VERSION 5.7 ;
  NOWIREEXTENSIONATPIN ON ;
  DIVIDERCHAR "/" ;
  BUSBITCHARS "[]" ;
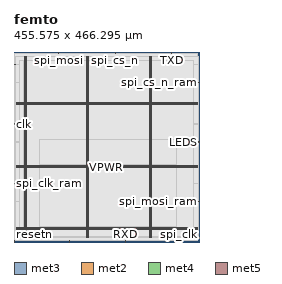
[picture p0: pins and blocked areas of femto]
MACRO femto
  CLASS BLOCK ;
  FOREIGN femto ;
  ORIGIN 0.000 0.000 ;
  SIZE 455.575 BY 466.295 ;
  PIN LEDS
    DIRECTION OUTPUT TRISTATE ;
    USE SIGNAL ;
    ANTENNADIFFAREA 0.445500 ;
    PORT
      LAYER met3 ;
        RECT 451.575 244.840 455.575 245.440 ;
    END
  END LEDS
  PIN RXD
    DIRECTION INPUT ;
    USE SIGNAL ;
    ANTENNAGATEAREA 0.213000 ;
    PORT
      LAYER met2 ;
        RECT 273.790 0.000 274.070 4.000 ;
    END
  END RXD
  PIN TXD
    DIRECTION OUTPUT TRISTATE ;
    USE SIGNAL ;
    ANTENNADIFFAREA 0.795200 ;
    PORT
      LAYER met2 ;
        RECT 386.490 462.295 386.770 466.295 ;
    END
  END TXD
  PIN VGND
    DIRECTION INOUT ;
    USE GROUND ;
    PORT
      LAYER met4 ;
        RECT 28.020 10.640 29.620 454.480 ;
    END
    PORT
      LAYER met4 ;
        RECT 181.620 10.640 183.220 454.480 ;
    END
    PORT
      LAYER met4 ;
        RECT 335.220 10.640 336.820 454.480 ;
    END
    PORT
      LAYER met5 ;
        RECT 5.280 33.380 450.120 34.980 ;
    END
    PORT
      LAYER met5 ;
        RECT 5.280 186.560 450.120 188.160 ;
    END
    PORT
      LAYER met5 ;
        RECT 5.280 339.740 450.120 341.340 ;
    END
  END VGND
  PIN VPWR
    DIRECTION INOUT ;
    USE POWER ;
    PORT
      LAYER met4 ;
        RECT 24.720 10.640 26.320 454.480 ;
    END
    PORT
      LAYER met4 ;
        RECT 178.320 10.640 179.920 454.480 ;
    END
    PORT
      LAYER met4 ;
        RECT 331.920 10.640 333.520 454.480 ;
    END
    PORT
      LAYER met5 ;
        RECT 5.280 30.080 450.120 31.680 ;
    END
    PORT
      LAYER met5 ;
        RECT 5.280 183.260 450.120 184.860 ;
    END
    PORT
      LAYER met5 ;
        RECT 5.280 336.440 450.120 338.040 ;
    END
  END VPWR
  PIN clk
    DIRECTION INPUT ;
    USE SIGNAL ;
    ANTENNAGATEAREA 0.852000 ;
    PORT
      LAYER met3 ;
        RECT 0.000 289.040 4.000 289.640 ;
    END
  END clk
  PIN resetn
    DIRECTION INPUT ;
    USE SIGNAL ;
    ANTENNAGATEAREA 0.159000 ;
    PORT
      LAYER met2 ;
        RECT 0.090 0.000 0.370 4.000 ;
    END
  END resetn
  PIN spi_clk
    DIRECTION OUTPUT TRISTATE ;
    USE SIGNAL ;
    ANTENNADIFFAREA 0.795200 ;
    PORT
      LAYER met2 ;
        RECT 412.250 0.000 412.530 4.000 ;
    END
  END spi_clk
  PIN spi_clk_ram
    DIRECTION OUTPUT TRISTATE ;
    USE SIGNAL ;
    ANTENNADIFFAREA 0.795200 ;
    PORT
      LAYER met3 ;
        RECT 0.000 142.840 4.000 143.440 ;
    END
  END spi_clk_ram
  PIN spi_cs_n
    DIRECTION OUTPUT TRISTATE ;
    USE SIGNAL ;
    ANTENNADIFFAREA 0.795200 ;
    PORT
      LAYER met2 ;
        RECT 248.030 462.295 248.310 466.295 ;
    END
  END spi_cs_n
  PIN spi_cs_n_ram
    DIRECTION OUTPUT TRISTATE ;
    USE SIGNAL ;
    ANTENNADIFFAREA 0.795200 ;
    PORT
      LAYER met3 ;
        RECT 451.575 391.040 455.575 391.640 ;
    END
  END spi_cs_n_ram
  PIN spi_miso
    DIRECTION INPUT ;
    USE SIGNAL ;
    ANTENNAGATEAREA 0.213000 ;
    PORT
      LAYER met2 ;
        RECT 135.330 0.000 135.610 4.000 ;
    END
  END spi_miso
  PIN spi_miso_ram
    DIRECTION INPUT ;
    USE SIGNAL ;
    ANTENNAGATEAREA 0.159000 ;
    PORT
      LAYER met3 ;
        RECT 0.000 435.240 4.000 435.840 ;
    END
  END spi_miso_ram
  PIN spi_mosi
    DIRECTION OUTPUT TRISTATE ;
    USE SIGNAL ;
    ANTENNADIFFAREA 0.795200 ;
    PORT
      LAYER met2 ;
        RECT 109.570 462.295 109.850 466.295 ;
    END
  END spi_mosi
  PIN spi_mosi_ram
    DIRECTION OUTPUT TRISTATE ;
    USE SIGNAL ;
    ANTENNADIFFAREA 0.795200 ;
    PORT
      LAYER met3 ;
        RECT 451.575 98.640 455.575 99.240 ;
    END
  END spi_mosi_ram
  OBS
      LAYER li1 ;
        RECT 5.520 10.795 449.880 454.325 ;
      LAYER met1 ;
        RECT 0.070 9.900 449.880 454.480 ;
      LAYER met2 ;
        RECT 0.100 462.015 109.290 462.810 ;
        RECT 110.130 462.015 247.750 462.810 ;
        RECT 248.590 462.015 386.210 462.810 ;
        RECT 387.050 462.015 449.790 462.810 ;
        RECT 0.100 4.280 449.790 462.015 ;
        RECT 0.650 3.670 135.050 4.280 ;
        RECT 135.890 3.670 273.510 4.280 ;
        RECT 274.350 3.670 411.970 4.280 ;
        RECT 412.810 3.670 449.790 4.280 ;
      LAYER met3 ;
        RECT 3.990 436.240 451.575 454.405 ;
        RECT 4.400 434.840 451.575 436.240 ;
        RECT 3.990 392.040 451.575 434.840 ;
        RECT 3.990 390.640 451.175 392.040 ;
        RECT 3.990 290.040 451.575 390.640 ;
        RECT 4.400 288.640 451.575 290.040 ;
        RECT 3.990 245.840 451.575 288.640 ;
        RECT 3.990 244.440 451.175 245.840 ;
        RECT 3.990 143.840 451.575 244.440 ;
        RECT 4.400 142.440 451.575 143.840 ;
        RECT 3.990 99.640 451.575 142.440 ;
        RECT 3.990 98.240 451.175 99.640 ;
        RECT 3.990 10.715 451.575 98.240 ;
      LAYER met4 ;
        RECT 13.175 12.415 24.320 444.545 ;
        RECT 26.720 12.415 27.620 444.545 ;
        RECT 30.020 12.415 177.920 444.545 ;
        RECT 180.320 12.415 181.220 444.545 ;
        RECT 183.620 12.415 331.520 444.545 ;
        RECT 333.920 12.415 334.820 444.545 ;
        RECT 337.220 12.415 440.385 444.545 ;
      LAYER met5 ;
        RECT 62.220 189.760 397.780 250.700 ;
        RECT 62.220 38.300 397.780 181.660 ;
  END
END femto
END LIBRARY

